VERSION 5.8 ;
BUSBITCHARS "[]" ;
DIVIDERCHAR "/" ;
UNITS
    DATABASE MICRONS 1000 ;
END UNITS

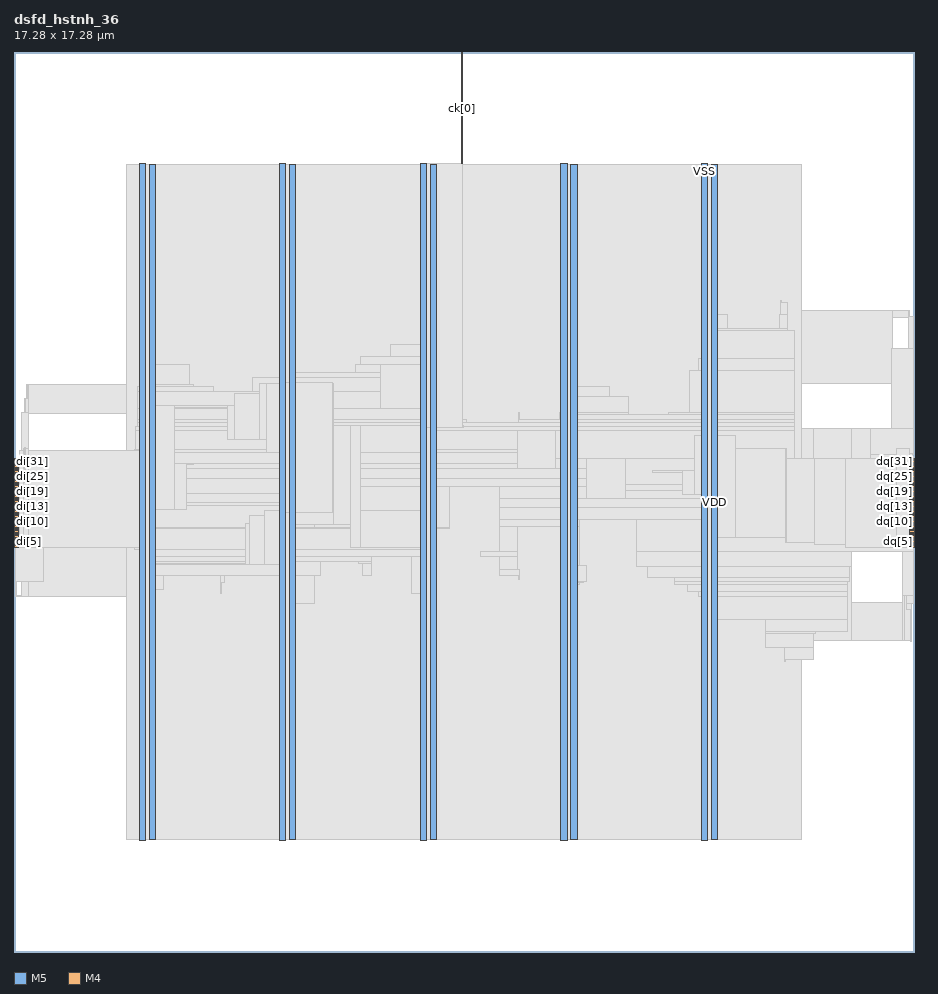
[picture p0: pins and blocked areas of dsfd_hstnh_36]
MACRO dsfd_hstnh_36
  FOREIGN dsfd_hstnh_36 0 0 ;
  CLASS BLOCK ;
  SIZE 17.28 BY 17.28 ;
  PIN ck[0]
    DIRECTION INPUT ;
    USE SIGNAL ;
    PORT
      LAYER M5 ;
        RECT  8.592 17.196 8.616 17.28 ;
    END
    PORT
      LAYER M5 ;
        RECT  8.592 15.143 8.616 17.232 ;
    END
  END ck[0]
  PIN di[0]
    DIRECTION INPUT ;
    USE SIGNAL ;
    PORT
      LAYER M4 ;
        RECT  0 7.776 0.084 7.8 ;
    END
  END di[0]
  PIN di[10]
    DIRECTION INPUT ;
    USE SIGNAL ;
    PORT
      LAYER M4 ;
        RECT  0 8.256 0.084 8.28 ;
    END
  END di[10]
  PIN di[11]
    DIRECTION INPUT ;
    USE SIGNAL ;
    PORT
      LAYER M4 ;
        RECT  0 8.304 0.084 8.328 ;
    END
  END di[11]
  PIN di[12]
    DIRECTION INPUT ;
    USE SIGNAL ;
    PORT
      LAYER M4 ;
        RECT  0 8.352 0.084 8.376 ;
    END
  END di[12]
  PIN di[13]
    DIRECTION INPUT ;
    USE SIGNAL ;
    PORT
      LAYER M4 ;
        RECT  0 8.4 0.084 8.424 ;
    END
  END di[13]
  PIN di[14]
    DIRECTION INPUT ;
    USE SIGNAL ;
    PORT
      LAYER M4 ;
        RECT  0 8.448 0.084 8.472 ;
    END
  END di[14]
  PIN di[15]
    DIRECTION INPUT ;
    USE SIGNAL ;
    PORT
      LAYER M4 ;
        RECT  0 8.496 0.084 8.52 ;
    END
  END di[15]
  PIN di[16]
    DIRECTION INPUT ;
    USE SIGNAL ;
    PORT
      LAYER M4 ;
        RECT  0 8.544 0.084 8.568 ;
    END
  END di[16]
  PIN di[17]
    DIRECTION INPUT ;
    USE SIGNAL ;
    PORT
      LAYER M4 ;
        RECT  0 8.592 0.084 8.616 ;
    END
  END di[17]
  PIN di[18]
    DIRECTION INPUT ;
    USE SIGNAL ;
    PORT
      LAYER M4 ;
        RECT  0 8.64 0.084 8.664 ;
    END
  END di[18]
  PIN di[19]
    DIRECTION INPUT ;
    USE SIGNAL ;
    PORT
      LAYER M4 ;
        RECT  0 8.688 0.084 8.712 ;
    END
  END di[19]
  PIN di[1]
    DIRECTION INPUT ;
    USE SIGNAL ;
    PORT
      LAYER M4 ;
        RECT  0 7.824 0.084 7.848 ;
    END
  END di[1]
  PIN di[20]
    DIRECTION INPUT ;
    USE SIGNAL ;
    PORT
      LAYER M4 ;
        RECT  0 8.736 0.084 8.76 ;
    END
  END di[20]
  PIN di[21]
    DIRECTION INPUT ;
    USE SIGNAL ;
    PORT
      LAYER M4 ;
        RECT  0 8.784 0.084 8.808 ;
    END
  END di[21]
  PIN di[22]
    DIRECTION INPUT ;
    USE SIGNAL ;
    PORT
      LAYER M4 ;
        RECT  0 8.832 0.084 8.856 ;
    END
  END di[22]
  PIN di[23]
    DIRECTION INPUT ;
    USE SIGNAL ;
    PORT
      LAYER M4 ;
        RECT  0 8.88 0.084 8.904 ;
    END
  END di[23]
  PIN di[24]
    DIRECTION INPUT ;
    USE SIGNAL ;
    PORT
      LAYER M4 ;
        RECT  0 8.928 0.084 8.952 ;
    END
  END di[24]
  PIN di[25]
    DIRECTION INPUT ;
    USE SIGNAL ;
    PORT
      LAYER M4 ;
        RECT  0 8.976 0.084 9 ;
    END
  END di[25]
  PIN di[26]
    DIRECTION INPUT ;
    USE SIGNAL ;
    PORT
      LAYER M4 ;
        RECT  0 9.024 0.084 9.048 ;
    END
  END di[26]
  PIN di[27]
    DIRECTION INPUT ;
    USE SIGNAL ;
    PORT
      LAYER M4 ;
        RECT  0 9.072 0.084 9.096 ;
    END
  END di[27]
  PIN di[28]
    DIRECTION INPUT ;
    USE SIGNAL ;
    PORT
      LAYER M4 ;
        RECT  0 9.12 0.084 9.144 ;
    END
  END di[28]
  PIN di[29]
    DIRECTION INPUT ;
    USE SIGNAL ;
    PORT
      LAYER M4 ;
        RECT  0 9.168 0.084 9.192 ;
    END
  END di[29]
  PIN di[2]
    DIRECTION INPUT ;
    USE SIGNAL ;
    PORT
      LAYER M4 ;
        RECT  0 7.872 0.084 7.896 ;
    END
  END di[2]
  PIN di[30]
    DIRECTION INPUT ;
    USE SIGNAL ;
    PORT
      LAYER M4 ;
        RECT  0 9.216 0.084 9.24 ;
    END
  END di[30]
  PIN di[31]
    DIRECTION INPUT ;
    USE SIGNAL ;
    PORT
      LAYER M4 ;
        RECT  0 9.264 0.084 9.288 ;
    END
  END di[31]
  PIN di[32]
    DIRECTION INPUT ;
    USE SIGNAL ;
    PORT
      LAYER M4 ;
        RECT  0 9.312 0.084 9.336 ;
    END
  END di[32]
  PIN di[33]
    DIRECTION INPUT ;
    USE SIGNAL ;
    PORT
      LAYER M4 ;
        RECT  0 9.36 0.084 9.384 ;
    END
  END di[33]
  PIN di[34]
    DIRECTION INPUT ;
    USE SIGNAL ;
    PORT
      LAYER M4 ;
        RECT  0 9.408 0.084 9.432 ;
    END
  END di[34]
  PIN di[35]
    DIRECTION INPUT ;
    USE SIGNAL ;
    PORT
      LAYER M4 ;
        RECT  0 9.456 0.084 9.48 ;
    END
  END di[35]
  PIN di[3]
    DIRECTION INPUT ;
    USE SIGNAL ;
    PORT
      LAYER M4 ;
        RECT  0 7.92 0.084 7.944 ;
    END
  END di[3]
  PIN di[4]
    DIRECTION INPUT ;
    USE SIGNAL ;
    PORT
      LAYER M4 ;
        RECT  0 7.968 0.084 7.992 ;
    END
  END di[4]
  PIN di[5]
    DIRECTION INPUT ;
    USE SIGNAL ;
    PORT
      LAYER M4 ;
        RECT  0 8.016 0.084 8.04 ;
    END
  END di[5]
  PIN di[6]
    DIRECTION INPUT ;
    USE SIGNAL ;
    PORT
      LAYER M4 ;
        RECT  0 8.064 0.084 8.088 ;
    END
  END di[6]
  PIN di[7]
    DIRECTION INPUT ;
    USE SIGNAL ;
    PORT
      LAYER M4 ;
        RECT  0 8.112 0.084 8.136 ;
    END
  END di[7]
  PIN di[8]
    DIRECTION INPUT ;
    USE SIGNAL ;
    PORT
      LAYER M4 ;
        RECT  0 8.16 0.084 8.184 ;
    END
  END di[8]
  PIN di[9]
    DIRECTION INPUT ;
    USE SIGNAL ;
    PORT
      LAYER M4 ;
        RECT  0 8.208 0.084 8.232 ;
    END
  END di[9]
  PIN dq[0]
    DIRECTION OUTPUT ;
    USE SIGNAL ;
    PORT
      LAYER M4 ;
        RECT  17.196 7.776 17.28 7.8 ;
    END
  END dq[0]
  PIN dq[10]
    DIRECTION OUTPUT ;
    USE SIGNAL ;
    PORT
      LAYER M4 ;
        RECT  17.196 8.256 17.28 8.28 ;
    END
  END dq[10]
  PIN dq[11]
    DIRECTION OUTPUT ;
    USE SIGNAL ;
    PORT
      LAYER M4 ;
        RECT  17.196 8.304 17.28 8.328 ;
    END
  END dq[11]
  PIN dq[12]
    DIRECTION OUTPUT ;
    USE SIGNAL ;
    PORT
      LAYER M4 ;
        RECT  17.196 8.352 17.28 8.376 ;
    END
  END dq[12]
  PIN dq[13]
    DIRECTION OUTPUT ;
    USE SIGNAL ;
    PORT
      LAYER M4 ;
        RECT  17.196 8.4 17.28 8.424 ;
    END
  END dq[13]
  PIN dq[14]
    DIRECTION OUTPUT ;
    USE SIGNAL ;
    PORT
      LAYER M4 ;
        RECT  17.196 8.448 17.28 8.472 ;
    END
  END dq[14]
  PIN dq[15]
    DIRECTION OUTPUT ;
    USE SIGNAL ;
    PORT
      LAYER M4 ;
        RECT  17.196 8.496 17.28 8.52 ;
    END
  END dq[15]
  PIN dq[16]
    DIRECTION OUTPUT ;
    USE SIGNAL ;
    PORT
      LAYER M4 ;
        RECT  17.196 8.544 17.28 8.568 ;
    END
  END dq[16]
  PIN dq[17]
    DIRECTION OUTPUT ;
    USE SIGNAL ;
    PORT
      LAYER M4 ;
        RECT  17.196 8.592 17.28 8.616 ;
    END
  END dq[17]
  PIN dq[18]
    DIRECTION OUTPUT ;
    USE SIGNAL ;
    PORT
      LAYER M4 ;
        RECT  17.196 8.64 17.28 8.664 ;
    END
  END dq[18]
  PIN dq[19]
    DIRECTION OUTPUT ;
    USE SIGNAL ;
    PORT
      LAYER M4 ;
        RECT  17.196 8.688 17.28 8.712 ;
    END
  END dq[19]
  PIN dq[1]
    DIRECTION OUTPUT ;
    USE SIGNAL ;
    PORT
      LAYER M4 ;
        RECT  17.196 7.824 17.28 7.848 ;
    END
  END dq[1]
  PIN dq[20]
    DIRECTION OUTPUT ;
    USE SIGNAL ;
    PORT
      LAYER M4 ;
        RECT  17.196 8.736 17.28 8.76 ;
    END
  END dq[20]
  PIN dq[21]
    DIRECTION OUTPUT ;
    USE SIGNAL ;
    PORT
      LAYER M4 ;
        RECT  17.196 8.784 17.28 8.808 ;
    END
  END dq[21]
  PIN dq[22]
    DIRECTION OUTPUT ;
    USE SIGNAL ;
    PORT
      LAYER M4 ;
        RECT  17.196 8.832 17.28 8.856 ;
    END
  END dq[22]
  PIN dq[23]
    DIRECTION OUTPUT ;
    USE SIGNAL ;
    PORT
      LAYER M4 ;
        RECT  17.196 8.88 17.28 8.904 ;
    END
  END dq[23]
  PIN dq[24]
    DIRECTION OUTPUT ;
    USE SIGNAL ;
    PORT
      LAYER M4 ;
        RECT  17.196 8.928 17.28 8.952 ;
    END
  END dq[24]
  PIN dq[25]
    DIRECTION OUTPUT ;
    USE SIGNAL ;
    PORT
      LAYER M4 ;
        RECT  17.196 8.976 17.28 9 ;
    END
  END dq[25]
  PIN dq[26]
    DIRECTION OUTPUT ;
    USE SIGNAL ;
    PORT
      LAYER M4 ;
        RECT  17.196 9.024 17.28 9.048 ;
    END
  END dq[26]
  PIN dq[27]
    DIRECTION OUTPUT ;
    USE SIGNAL ;
    PORT
      LAYER M4 ;
        RECT  17.196 9.072 17.28 9.096 ;
    END
  END dq[27]
  PIN dq[28]
    DIRECTION OUTPUT ;
    USE SIGNAL ;
    PORT
      LAYER M4 ;
        RECT  17.196 9.12 17.28 9.144 ;
    END
  END dq[28]
  PIN dq[29]
    DIRECTION OUTPUT ;
    USE SIGNAL ;
    PORT
      LAYER M4 ;
        RECT  17.196 9.168 17.28 9.192 ;
    END
  END dq[29]
  PIN dq[2]
    DIRECTION OUTPUT ;
    USE SIGNAL ;
    PORT
      LAYER M4 ;
        RECT  17.196 7.872 17.28 7.896 ;
    END
  END dq[2]
  PIN dq[30]
    DIRECTION OUTPUT ;
    USE SIGNAL ;
    PORT
      LAYER M4 ;
        RECT  17.196 9.216 17.28 9.24 ;
    END
  END dq[30]
  PIN dq[31]
    DIRECTION OUTPUT ;
    USE SIGNAL ;
    PORT
      LAYER M4 ;
        RECT  17.196 9.264 17.28 9.288 ;
    END
  END dq[31]
  PIN dq[32]
    DIRECTION OUTPUT ;
    USE SIGNAL ;
    PORT
      LAYER M4 ;
        RECT  17.196 9.312 17.28 9.336 ;
    END
  END dq[32]
  PIN dq[33]
    DIRECTION OUTPUT ;
    USE SIGNAL ;
    PORT
      LAYER M4 ;
        RECT  17.196 9.36 17.28 9.384 ;
    END
  END dq[33]
  PIN dq[34]
    DIRECTION OUTPUT ;
    USE SIGNAL ;
    PORT
      LAYER M4 ;
        RECT  17.196 9.408 17.28 9.432 ;
    END
  END dq[34]
  PIN dq[35]
    DIRECTION OUTPUT ;
    USE SIGNAL ;
    PORT
      LAYER M4 ;
        RECT  17.196 9.456 17.28 9.48 ;
    END
  END dq[35]
  PIN dq[3]
    DIRECTION OUTPUT ;
    USE SIGNAL ;
    PORT
      LAYER M4 ;
        RECT  17.196 7.92 17.28 7.944 ;
    END
  END dq[3]
  PIN dq[4]
    DIRECTION OUTPUT ;
    USE SIGNAL ;
    PORT
      LAYER M4 ;
        RECT  17.196 7.968 17.28 7.992 ;
    END
  END dq[4]
  PIN dq[5]
    DIRECTION OUTPUT ;
    USE SIGNAL ;
    PORT
      LAYER M4 ;
        RECT  17.196 8.016 17.28 8.04 ;
    END
  END dq[5]
  PIN dq[6]
    DIRECTION OUTPUT ;
    USE SIGNAL ;
    PORT
      LAYER M4 ;
        RECT  17.196 8.064 17.28 8.088 ;
    END
  END dq[6]
  PIN dq[7]
    DIRECTION OUTPUT ;
    USE SIGNAL ;
    PORT
      LAYER M4 ;
        RECT  17.196 8.112 17.28 8.136 ;
    END
  END dq[7]
  PIN dq[8]
    DIRECTION OUTPUT ;
    USE SIGNAL ;
    PORT
      LAYER M4 ;
        RECT  17.196 8.16 17.28 8.184 ;
    END
  END dq[8]
  PIN dq[9]
    DIRECTION OUTPUT ;
    USE SIGNAL ;
    PORT
      LAYER M4 ;
        RECT  17.196 8.208 17.28 8.232 ;
    END
  END dq[9]
  PIN VDD
    DIRECTION INOUT ;
    USE POWER ;
    PORT
      LAYER M5 ;
        RECT  13.392 2.151 13.512 15.129 ;
        RECT  10.692 2.151 10.812 15.129 ;
        RECT  7.992 2.151 8.112 15.129 ;
        RECT  5.292 2.151 5.412 15.129 ;
        RECT  2.592 2.151 2.712 15.129 ;
    END
  END VDD
  PIN VSS
    DIRECTION INOUT ;
    USE GROUND ;
    PORT
      LAYER M5 ;
        RECT  13.2 2.137 13.32 15.143 ;
        RECT  10.5 2.137 10.62 15.143 ;
        RECT  7.8 2.137 7.92 15.143 ;
        RECT  5.1 2.137 5.22 15.143 ;
        RECT  2.4 2.137 2.52 15.143 ;
    END
  END VSS
  # OT_OBS_CLOSED layer=M5 d_um=1.536 added=0
  OBS
    LAYER RVTN ;
     RECT  2.16 2.16 15.12 2.295 ;
     RECT  2.16 2.565 15.12 2.835 ;
     RECT  2.16 3.105 15.12 3.375 ;
     RECT  2.16 3.645 15.12 3.915 ;
     RECT  2.16 4.185 15.12 4.455 ;
     RECT  2.16 4.725 15.12 4.995 ;
     RECT  2.16 5.265 15.12 5.535 ;
     RECT  2.16 5.805 15.12 6.075 ;
     RECT  2.16 6.345 15.12 6.615 ;
     RECT  2.16 6.885 15.12 7.155 ;
     RECT  2.16 7.425 15.12 7.695 ;
     RECT  2.16 7.965 15.12 8.235 ;
     RECT  2.16 8.505 15.12 8.775 ;
     RECT  2.16 9.045 15.12 9.315 ;
     RECT  2.16 9.585 15.12 9.855 ;
     RECT  2.16 10.125 15.12 10.395 ;
     RECT  2.16 10.665 15.12 10.935 ;
     RECT  2.16 11.205 15.12 11.475 ;
     RECT  2.16 11.745 15.12 12.015 ;
     RECT  2.16 12.285 15.12 12.555 ;
     RECT  2.16 12.825 15.12 13.095 ;
     RECT  2.16 13.365 15.12 13.635 ;
     RECT  2.16 13.905 15.12 14.175 ;
     RECT  2.16 14.445 15.12 14.715 ;
     RECT  2.16 14.985 15.12 15.12 ;
    LAYER RVTP ;
     RECT  2.16 2.295 15.12 2.565 ;
     RECT  2.16 2.835 15.12 3.105 ;
     RECT  2.16 3.375 15.12 3.645 ;
     RECT  2.16 3.915 15.12 4.185 ;
     RECT  2.16 4.455 15.12 4.725 ;
     RECT  2.16 4.995 15.12 5.265 ;
     RECT  2.16 5.535 15.12 5.805 ;
     RECT  2.16 6.075 15.12 6.345 ;
     RECT  2.16 6.615 15.12 6.885 ;
     RECT  2.16 7.155 15.12 7.425 ;
     RECT  2.16 7.695 15.12 7.965 ;
     RECT  2.16 8.235 15.12 8.505 ;
     RECT  2.16 8.775 15.12 9.045 ;
     RECT  2.16 9.315 15.12 9.585 ;
     RECT  2.16 9.855 15.12 10.125 ;
     RECT  2.16 10.395 15.12 10.665 ;
     RECT  2.16 10.935 15.12 11.205 ;
     RECT  2.16 11.475 15.12 11.745 ;
     RECT  2.16 12.015 15.12 12.285 ;
     RECT  2.16 12.555 15.12 12.825 ;
     RECT  2.16 13.095 15.12 13.365 ;
     RECT  2.16 13.635 15.12 13.905 ;
     RECT  2.16 14.175 15.12 14.445 ;
     RECT  2.16 14.715 15.12 14.985 ;
    LAYER M1 ;
     RECT  2.16 2.151 15.12 15.129 ;
    LAYER M2 ;
     RECT  0.031 6.822 0.139 6.84 ;
     RECT  0.031 7.902 0.139 7.92 ;
     RECT  0.103 9.126 0.175 9.144 ;
     RECT  0.139 10.332 0.211 10.35 ;
     RECT  0.211 10.332 0.247 10.62 ;
     RECT  0.139 6.822 0.283 7.92 ;
     RECT  0.175 9.054 0.383 9.306 ;
     RECT  0.383 9.288 0.419 9.306 ;
     RECT  0.283 6.822 2.16 7.956 ;
     RECT  0.247 10.332 2.16 10.89 ;
     RECT  2.16 2.151 15.12 15.129 ;
     RECT  15.12 5.616 15.359 10.044 ;
     RECT  15.359 5.976 16.079 10.044 ;
     RECT  16.079 7.704 16.475 10.044 ;
     RECT  16.475 7.704 16.511 9.918 ;
     RECT  16.511 7.704 16.547 9.108 ;
     RECT  15.12 10.908 16.871 12.312 ;
     RECT  16.511 9.9 17.015 9.918 ;
     RECT  16.871 10.908 17.023 11.394 ;
     RECT  16.079 5.976 17.059 6.714 ;
     RECT  17.059 5.976 17.095 6.876 ;
     RECT  16.547 8.514 17.123 9.108 ;
     RECT  17.023 10.791 17.123 11.394 ;
     RECT  16.871 12.186 17.195 12.312 ;
     RECT  17.095 5.976 17.231 6.948 ;
     RECT  17.231 6.696 17.267 6.714 ;
     RECT  17.123 8.514 17.267 8.532 ;
     RECT  17.195 12.186 17.267 12.204 ;
    LAYER M3 ;
     RECT  2.415 2.143 2.505 2.413 ;
     RECT  5.115 2.143 5.205 2.413 ;
     RECT  7.815 2.143 7.905 2.413 ;
     RECT  10.515 2.143 10.605 2.413 ;
     RECT  13.215 2.143 13.305 2.413 ;
     RECT  14.796 5.575 14.814 5.611 ;
     RECT  14.796 5.611 15.354 5.845 ;
     RECT  14.436 5.845 15.354 6.115 ;
     RECT  14.436 6.115 15.39 6.151 ;
     RECT  13.215 2.413 13.497 6.385 ;
     RECT  14.436 6.151 16.002 6.385 ;
     RECT  17.208 5.971 17.226 6.583 ;
     RECT  5.115 2.413 5.397 6.691 ;
     RECT  17.136 6.583 17.226 6.691 ;
     RECT  13.215 6.385 16.002 6.817 ;
     RECT  17.136 6.691 17.262 6.853 ;
     RECT  7.815 2.413 8.097 6.889 ;
     RECT  13.14 6.817 16.002 6.925 ;
     RECT  2.415 2.413 2.697 6.961 ;
     RECT  10.515 2.413 10.797 7.051 ;
     RECT  12.924 6.925 16.002 7.051 ;
     RECT  3.96 6.889 3.978 7.087 ;
     RECT  10.515 7.051 10.854 7.087 ;
     RECT  0.036 6.817 0.054 7.123 ;
     RECT  10.515 7.087 10.926 7.123 ;
     RECT  12.672 7.051 16.002 7.123 ;
     RECT  12.672 7.123 16.038 7.195 ;
     RECT  2.415 6.961 2.862 7.231 ;
     RECT  3.96 7.087 4.05 7.231 ;
     RECT  5.115 6.691 5.778 7.231 ;
     RECT  9.684 7.159 9.702 7.231 ;
     RECT  9.324 7.231 9.702 7.349 ;
     RECT  12.168 7.195 16.038 7.393 ;
     RECT  10.515 7.123 10.998 7.421 ;
     RECT  6.696 7.231 6.858 7.465 ;
     RECT  2.415 7.231 5.886 7.501 ;
     RECT  6.624 7.465 6.858 7.501 ;
     RECT  2.415 7.501 6.858 7.591 ;
     RECT  7.632 6.889 8.097 7.591 ;
     RECT  9.324 7.349 9.666 7.591 ;
     RECT  8.964 7.591 9.666 7.691 ;
     RECT  11.952 7.393 16.074 7.699 ;
     RECT  17.064 6.853 17.262 7.699 ;
     RECT  2.415 7.591 8.097 7.735 ;
     RECT  0.036 7.123 0.558 7.925 ;
     RECT  0.144 7.925 0.558 8.045 ;
     RECT  2.304 7.735 8.097 8.131 ;
     RECT  2.304 8.131 8.37 8.159 ;
     RECT  9.324 7.691 9.666 8.167 ;
     RECT  10.515 7.421 10.854 8.167 ;
     RECT  9.324 8.167 10.854 8.311 ;
     RECT  11.952 7.699 17.262 8.311 ;
     RECT  9.324 8.311 17.262 8.525 ;
     RECT  16.452 8.525 17.262 8.537 ;
     RECT  2.304 8.159 5.778 8.581 ;
     RECT  2.268 8.581 5.778 8.635 ;
     RECT  9.324 8.525 15.462 8.699 ;
     RECT  2.196 8.635 5.778 8.807 ;
     RECT  11.736 8.699 15.462 8.861 ;
     RECT  0.144 8.045 0.342 8.875 ;
     RECT  6.624 8.159 8.37 8.941 ;
     RECT  9.324 8.699 10.998 8.941 ;
     RECT  11.736 8.861 15.03 8.969 ;
     RECT  0.144 8.875 0.378 9.067 ;
     RECT  2.232 8.807 5.778 9.085 ;
     RECT  6.624 8.941 10.998 9.085 ;
     RECT  2.232 9.085 10.998 9.275 ;
     RECT  0.108 9.067 0.378 9.283 ;
     RECT  2.232 9.275 9.666 9.383 ;
     RECT  0.108 9.283 0.414 9.389 ;
     RECT  10.404 9.275 10.998 9.481 ;
     RECT  11.736 8.969 14.994 9.481 ;
     RECT  0.108 9.389 0.306 9.533 ;
     RECT  16.452 8.537 17.118 9.547 ;
     RECT  2.268 9.383 9.666 9.581 ;
     RECT  0.108 9.533 0.27 9.629 ;
     RECT  2.304 9.581 9.666 9.653 ;
     RECT  2.34 9.653 9.666 10.021 ;
     RECT  10.404 9.481 14.994 10.021 ;
     RECT  16.452 9.547 17.262 10.049 ;
     RECT  2.34 10.021 14.994 10.085 ;
     RECT  2.376 10.085 14.994 10.157 ;
     RECT  2.376 10.157 8.694 10.229 ;
     RECT  9.684 10.157 14.994 10.229 ;
     RECT  10.476 10.229 14.994 10.319 ;
     RECT  0.144 9.629 0.27 10.355 ;
     RECT  9.684 10.229 9.702 10.355 ;
     RECT  10.476 10.319 11.79 10.355 ;
     RECT  12.564 10.319 14.994 10.355 ;
     RECT  2.376 10.229 8.097 10.427 ;
     RECT  0.216 10.355 0.27 10.625 ;
     RECT  10.515 10.355 11.79 10.661 ;
     RECT  2.376 10.427 7.038 10.769 ;
     RECT  2.376 10.769 3.834 10.859 ;
     RECT  10.515 10.661 11.43 10.859 ;
     RECT  0.252 10.625 0.27 10.895 ;
     RECT  2.415 10.859 3.438 10.895 ;
     RECT  4.572 10.769 7.038 11.039 ;
     RECT  5.115 11.039 7.038 11.129 ;
     RECT  12.96 10.355 14.994 11.165 ;
     RECT  2.415 10.895 3.366 11.273 ;
     RECT  6.552 11.129 7.038 11.273 ;
     RECT  6.66 11.273 7.038 11.281 ;
     RECT  7.815 10.427 8.097 11.281 ;
     RECT  13.14 11.165 14.994 11.399 ;
     RECT  6.66 11.281 8.097 11.435 ;
     RECT  16.848 10.049 17.262 11.579 ;
     RECT  7.236 11.435 8.097 11.669 ;
     RECT  13.215 11.399 14.994 11.939 ;
     RECT  13.215 11.939 14.85 11.975 ;
     RECT  17.172 11.579 17.262 12.209 ;
     RECT  13.215 11.975 13.698 12.245 ;
     RECT  14.688 11.975 14.85 12.245 ;
     RECT  17.172 12.209 17.19 12.317 ;
     RECT  14.724 12.245 14.85 12.479 ;
     RECT  14.724 12.479 14.742 12.515 ;
     RECT  2.415 11.273 2.697 14.867 ;
     RECT  5.115 11.129 5.397 14.867 ;
     RECT  7.815 11.669 8.097 14.867 ;
     RECT  10.515 10.859 10.797 14.867 ;
     RECT  13.215 12.245 13.497 14.867 ;
     RECT  2.415 14.867 2.505 15.137 ;
     RECT  5.115 14.867 5.205 15.137 ;
     RECT  7.815 14.867 7.905 15.137 ;
     RECT  10.515 14.867 10.605 15.137 ;
     RECT  13.215 14.867 13.305 15.137 ;
    LAYER M4 ;
     RECT  0.06 7.776 0.097 9.48 ;
     RECT  0.097 7.776 0.181 9.624 ;
     RECT  0.181 7.776 0.281 9.672 ;
     RECT  0.281 7.776 2.408 9.624 ;
     RECT  2.408 2.148 2.512 15.132 ;
     RECT  2.512 2.418 2.704 14.862 ;
     RECT  2.704 8.496 3.089 10.488 ;
     RECT  3.089 8.496 3.305 9.384 ;
     RECT  3.305 9.36 3.449 9.384 ;
     RECT  3.089 10.464 4.093 10.488 ;
     RECT  4.093 9.84 4.237 10.488 ;
     RECT  2.704 7.44 4.453 7.464 ;
     RECT  4.453 7.44 4.525 8.232 ;
     RECT  4.237 9.84 4.705 10.728 ;
     RECT  4.525 7.44 4.813 8.376 ;
     RECT  4.705 9.84 4.849 10.92 ;
     RECT  4.813 7.44 5.108 8.472 ;
     RECT  4.849 9.6 5.108 10.92 ;
     RECT  5.108 2.148 5.212 15.132 ;
     RECT  5.212 2.418 5.404 14.862 ;
     RECT  5.404 8.208 6.131 10.92 ;
     RECT  6.131 8.208 6.469 10.104 ;
     RECT  6.469 7.776 6.653 10.104 ;
     RECT  6.653 7.776 7.808 8.472 ;
     RECT  6.653 9.6 7.808 10.104 ;
     RECT  7.808 2.148 7.912 15.132 ;
     RECT  7.912 2.418 8.104 14.862 ;
     RECT  8.104 10.08 8.627 10.104 ;
     RECT  10.508 2.148 10.612 15.132 ;
     RECT  10.612 2.418 10.804 14.862 ;
     RECT  12.265 9.216 12.841 9.24 ;
     RECT  12.841 8.784 13.057 9.24 ;
     RECT  13.057 8.784 13.208 9.912 ;
     RECT  13.208 2.148 13.312 15.132 ;
     RECT  13.312 2.418 13.504 14.862 ;
     RECT  13.504 7.968 13.853 9.912 ;
     RECT  13.853 7.968 14.821 9.672 ;
     RECT  14.821 7.872 14.825 9.672 ;
     RECT  14.825 7.872 15.361 9.48 ;
     RECT  15.361 7.824 15.973 9.48 ;
     RECT  15.973 7.776 16.945 9.48 ;
     RECT  16.945 7.776 17.201 9.672 ;
     RECT  17.201 7.776 17.244 9.576 ;
     RECT  17.244 9.552 17.273 9.576 ;
    LAYER M5 ;
     RECT  2.4 2.137 2.52 2.151 ;
     RECT  5.1 2.137 5.22 2.151 ;
     RECT  7.8 2.137 7.92 2.151 ;
     RECT  10.5 2.137 10.62 2.151 ;
     RECT  13.2 2.137 13.32 2.151 ;
     RECT  5.1 2.151 5.412 8.437 ;
     RECT  0.192 9.013 0.216 9.349 ;
     RECT  0.192 9.349 0.312 9.491 ;
     RECT  0.192 9.491 0.216 9.683 ;
     RECT  7.8 2.151 8.112 10.069 ;
     RECT  5.1 8.437 6.12 10.931 ;
     RECT  2.4 2.151 2.712 15.129 ;
     RECT  5.1 10.931 5.412 15.129 ;
     RECT  10.5 2.151 10.812 15.129 ;
     RECT  13.2 2.151 13.512 15.129 ;
     RECT  2.4 15.129 2.52 15.143 ;
     RECT  5.1 15.129 5.22 15.143 ;
     RECT  7.8 10.069 8.616 15.143 ;
     RECT  10.5 15.129 10.62 15.143 ;
     RECT  13.2 15.129 13.32 15.143 ;
  END
END dsfd_hstnh_36
END LIBRARY
